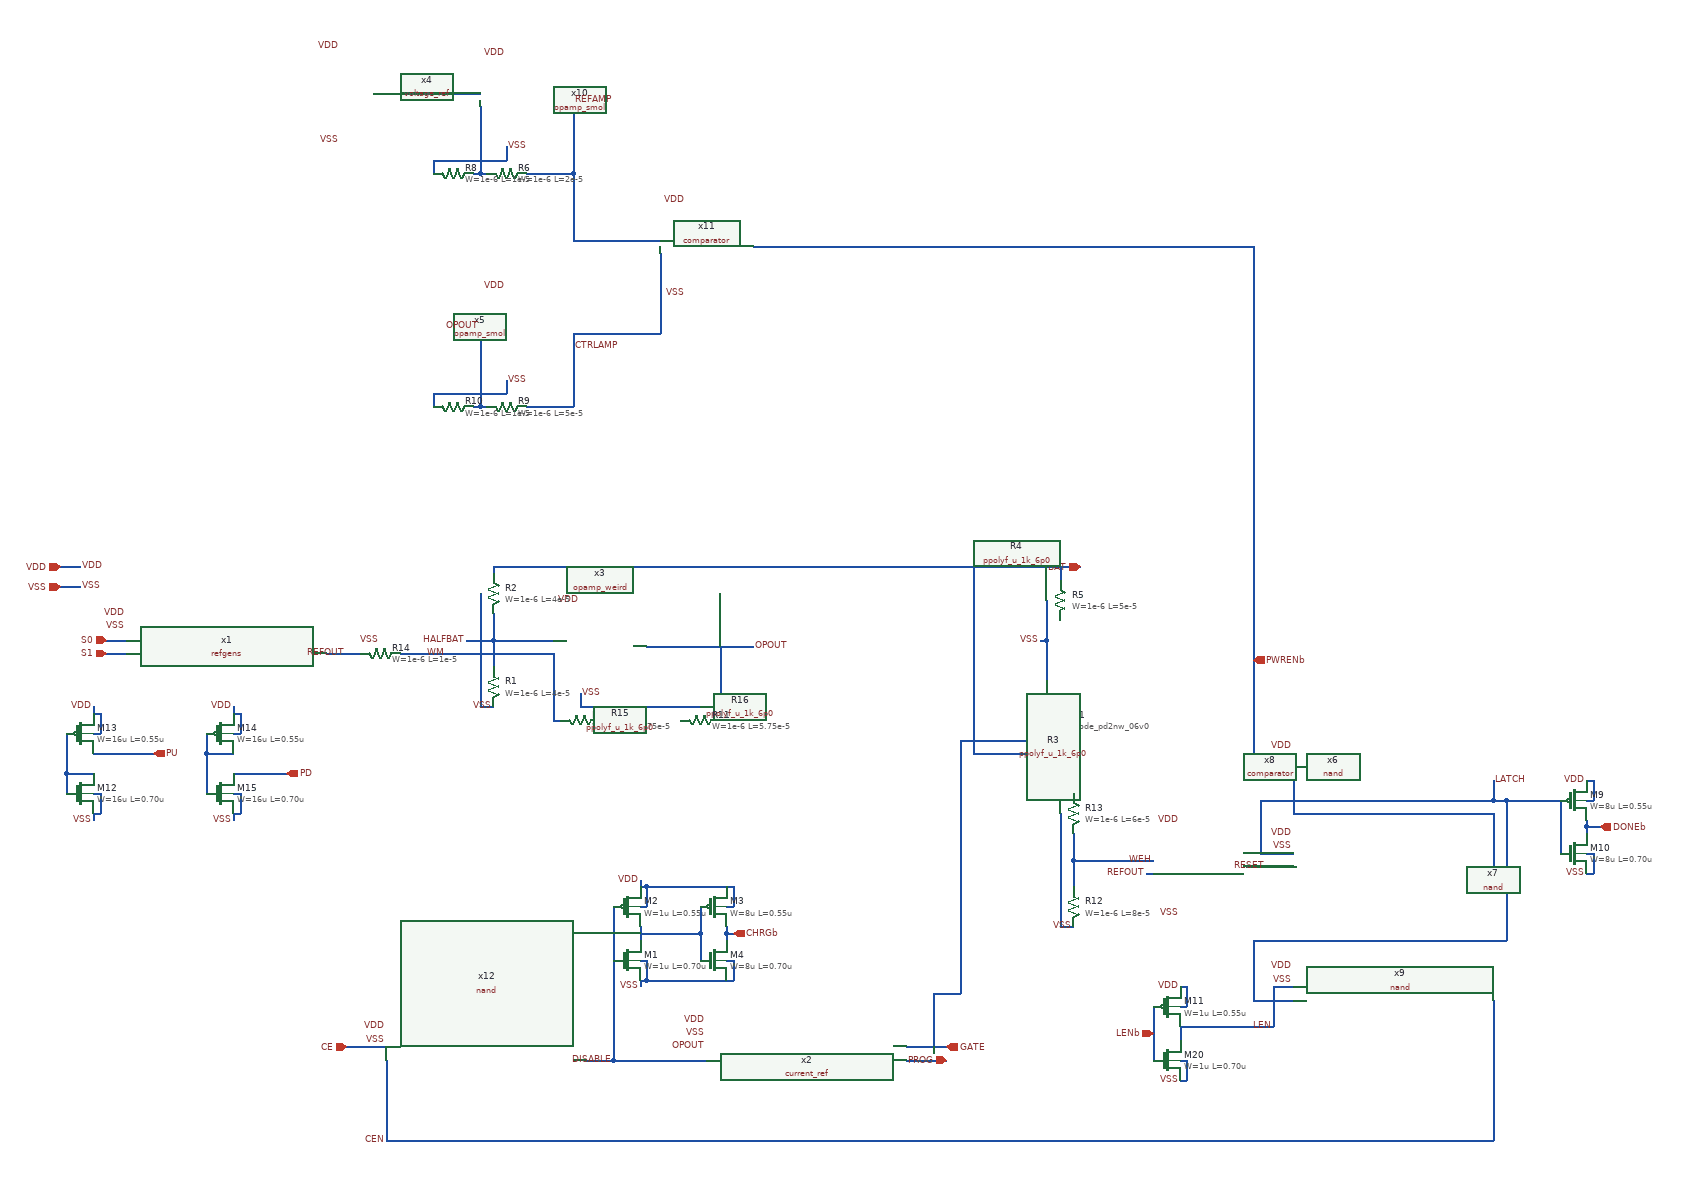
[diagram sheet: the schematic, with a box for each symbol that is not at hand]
v {xschem version=3.4.8RC file_version=1.3}
G {}
K {}
V {}
S {}
F {}
E {}
N -110 -10 -80 -10 {lab=VDD}
N -110 20 -80 20 {lab=VSS}
N -40 100 -10 100 {lab=S0}
N -40 120 -10 120 {lab=S1}
N 1160 710 1220 710 {lab=GATE}
N 720 730 860 730 {lab=DISABLE}
N 520 170 520 200 {lab=VSS}
N 520 200 540 200 {lab=VSS}
N 540 100 630 100 {lab=HALFBAT}
N 540 100 540 140 {lab=HALFBAT}
N 520 30 520 170 {lab=VSS}
N 540 60 540 100 {lab=HALFBAT}
N 540 -10 540 -0 {lab=BAT}
N 500 100 540 100 {lab=HALFBAT}
N 1360 100 1370 100 {lab=VSS}
N 1370 40 1370 100 {lab=VSS}
N 1370 100 1370 160 {lab=VSS}
N -60 360 -60 370 {lab=VSS}
N -100 300 -100 330 {lab=#net1}
N -100 300 -60 300 {lab=#net1}
N -60 360 -50 360 {lab=VSS}
N -50 330 -50 360 {lab=VSS}
N -60 330 -50 330 {lab=VSS}
N -100 240 -100 300 {lab=#net1}
N -60 240 -50 240 {lab=VDD}
N -50 210 -50 240 {lab=VDD}
N -60 210 -50 210 {lab=VDD}
N -60 200 -60 210 {lab=VDD}
N -60 270 30 270 {lab=PU}
N 150 200 150 210 {lab=VDD}
N 150 240 160 240 {lab=VDD}
N 160 210 160 240 {lab=VDD}
N 150 210 160 210 {lab=VDD}
N 110 240 110 270 {lab=#net2}
N 110 270 150 270 {lab=#net2}
N 110 270 110 330 {lab=#net2}
N 150 330 160 330 {lab=VSS}
N 160 330 160 360 {lab=VSS}
N 150 360 160 360 {lab=VSS}
N 150 360 150 370 {lab=VSS}
N 150 300 230 300 {lab=PD}
N 290 120 300 120 {lab=REFOUT}
N 1160 730 1220 730 {lab=PROG}
N 300 120 320 120 {lab=REFOUT}
N 540 -10 1420 -10 {lab=BAT}
N 2040 310 2040 340 {lab=LATCH}
N 1690 340 2040 340 {lab=LATCH}
N 1690 340 1690 420 {lab=LATCH}
N 1690 420 1740 420 {lab=LATCH}
N 1740 310 1740 360 {lab=#net3}
N 1740 360 2040 360 {lab=#net3}
N 2040 360 2040 440 {lab=#net3}
N 1670 440 1740 440 {lab=RESET}
N 1390 500 1390 530 {lab=VSS}
N 1390 530 1410 530 {lab=VSS}
N 1410 430 1410 470 {lab=WEH}
N 1390 360 1390 500 {lab=VSS}
N 1410 390 1410 430 {lab=WEH}
N 1410 320 1410 330 {lab=BAT}
N 1410 270 1410 320 {lab=BAT}
N 1260 270 1410 270 {lab=BAT}
N 1260 -10 1260 270 {lab=BAT}
N 1410 430 1530 430 {lab=WEH}
N 1520 450 1530 450 {lab=REFOUT}
N 1680 230 1680 290 {lab=PWRENb}
N 1680 290 1740 290 {lab=PWRENb}
N 2040 340 2060 340 {lab=LATCH}
N 2060 340 2060 550 {lab=LATCH}
N 1680 550 2060 550 {lab=LATCH}
N 2180 380 2200 380 {lab=DONEb}
N 2180 370 2180 380 {lab=DONEb}
N 2180 380 2180 390 {lab=DONEb}
N 2140 340 2140 420 {lab=LATCH}
N 2060 340 2140 340 {lab=LATCH}
N 2180 340 2190 340 {lab=VDD}
N 2190 310 2190 340 {lab=VDD}
N 2180 310 2190 310 {lab=VDD}
N 2180 450 2190 450 {lab=VSS}
N 2190 420 2190 450 {lab=VSS}
N 2180 420 2190 420 {lab=VSS}
N 1570 680 1570 700 {lab=#net4}
N 1570 650 1580 650 {lab=VDD}
N 1580 620 1580 650 {lab=VDD}
N 1570 620 1580 620 {lab=VDD}
N 1570 730 1580 730 {lab=VSS}
N 1580 730 1580 760 {lab=VSS}
N 1570 760 1580 760 {lab=VSS}
N 1530 650 1530 730 {lab=LENb}
N 1390 -10 1390 10 {lab=BAT}
N 1680 130 1680 230 {lab=PWRENb}
N 320 120 340 120 {lab=REFOUT}
N 400 120 630 120 {lab=WM}
N 670 180 670 200 {lab=VSS}
N 630 220 640 220 {lab=WM}
N 630 120 630 220 {lab=WM}
N 770 110 930 110 {lab=OPOUT}
N 880 110 880 220 {lab=OPOUT}
N 360 -720 520 -720 {lab=#net5}
N 560 -640 560 -620 {lab=VSS}
N 520 -700 520 -600 {lab=#net6}
N 510 -600 520 -600 {lab=#net6}
N 520 -600 530 -600 {lab=#net6}
N 480 -620 560 -620 {lab=VSS}
N 450 -620 480 -620 {lab=VSS}
N 450 -620 450 -600 {lab=VSS}
N 660 -710 660 -600 {lab=REFAMP}
N 590 -600 660 -600 {lab=REFAMP}
N 560 -290 560 -270 {lab=VSS}
N 520 -350 520 -250 {lab=#net7}
N 510 -250 520 -250 {lab=#net7}
N 520 -250 530 -250 {lab=#net7}
N 480 -270 560 -270 {lab=VSS}
N 450 -270 480 -270 {lab=VSS}
N 450 -270 450 -250 {lab=VSS}
N 660 -360 660 -250 {lab=CTRLAMP}
N 590 -250 660 -250 {lab=CTRLAMP}
N 1680 -490 1680 130 {lab=PWRENb}
N 930 -490 1680 -490 {lab=PWRENb}
N 660 -500 790 -500 {lab=REFAMP}
N 660 -600 660 -500 {lab=REFAMP}
N 660 -360 790 -360 {lab=CTRLAMP}
N 790 -480 790 -360 {lab=CTRLAMP}
N 670 200 790 200 {lab=VSS}
N 790 200 850 200 {lab=VSS}
N 680 730 720 730 {lab=DISABLE}
N 320 710 380 710 {lab=CE}
N 2040 640 2040 850 {lab=#net8}
N 380 850 2040 850 {lab=#net8}
N 380 730 380 850 {lab=#net8}
N 720 500 720 730 {lab=DISABLE}
N 760 610 760 620 {lab=VSS}
N 760 610 770 610 {lab=VSS}
N 770 580 770 610 {lab=VSS}
N 760 580 770 580 {lab=VSS}
N 760 460 760 470 {lab=VDD}
N 760 470 770 470 {lab=VDD}
N 770 470 770 500 {lab=VDD}
N 760 500 770 500 {lab=VDD}
N 760 530 760 550 {lab=#net9}
N 770 470 890 470 {lab=VDD}
N 890 500 900 500 {lab=VDD}
N 900 470 900 500 {lab=VDD}
N 890 470 900 470 {lab=VDD}
N 770 610 890 610 {lab=VSS}
N 890 610 900 610 {lab=VSS}
N 900 580 900 610 {lab=VSS}
N 890 580 900 580 {lab=VSS}
N 760 540 850 540 {lab=#net9}
N 850 500 850 540 {lab=#net9}
N 850 540 850 580 {lab=#net9}
N 890 540 900 540 {lab=CHRGb}
N 890 530 890 540 {lab=CHRGb}
N 890 540 890 550 {lab=CHRGb}
N 1570 680 1710 680 {lab=#net4}
N 1710 620 1710 680 {lab=#net4}
N 1710 620 1740 620 {lab=#net4}
N 1680 550 1680 640 {lab=LATCH}
N 1680 640 1740 640 {lab=LATCH}
N 1240 250 1390 250 {lab=GATE}
N 1240 250 1240 630 {lab=GATE}
N 1200 630 1240 630 {lab=GATE}
N 1200 630 1200 710 {lab=GATE}
C {iopin.sym} -110 -10 2 0 {name=p1 lab=VDD}
C {lab_pin.sym} -80 -10 2 0 {name=p2 sig_type=std_logic lab=VDD}
C {iopin.sym} -110 20 2 0 {name=p3 lab=VSS}
C {lab_pin.sym} -80 20 2 0 {name=p4 sig_type=std_logic lab=VSS}
C {ipin.sym} -40 100 0 0 {name=p5 lab=S0}
C {ipin.sym} -40 120 0 0 {name=p6 lab=S1}
C {ipin.sym} 1530 690 0 0 {name=p7 lab=LENb}
C {ipin.sym} 320 710 0 0 {name=p8 lab=CE}
C {opin.sym} 900 540 0 0 {name=p9 lab=CHRGb}
C {opin.sym} 2200 380 0 0 {name=p10 lab=DONEb}
C {iopin.sym} 1220 730 0 0 {name=p11 lab=PROG}
C {opin.sym} 1680 130 0 0 {name=p12 lab=PWRENb}
C {refgens.sym} 140 100 0 0 {name=x1}
C {lab_pin.sym} -10 60 0 0 {name=p13 sig_type=std_logic lab=VDD}
C {lab_pin.sym} -10 80 0 0 {name=p14 sig_type=std_logic lab=VSS}
C {opin.sym} 1220 710 0 0 {name=p15 lab=GATE}
C {ipin.sym} 1420 -10 2 0 {name=p16 lab=BAT}
C {current_ref.sym} 1010 700 0 0 {name=x2}
C {lab_pin.sym} 860 670 0 0 {name=p17 sig_type=std_logic lab=VDD}
C {lab_pin.sym} 670 40 1 0 {name=p23 sig_type=std_logic lab=VDD}
C {lab_pin.sym} 670 180 2 0 {name=p24 sig_type=std_logic lab=VSS}
C {symbols/ppolyf_u_1k_6p0.sym} 540 170 0 0 {name=R1
W=1e-6
L=4e-5
model=ppolyf_u_1k_6p0
spiceprefix=X
m=1}
C {lab_pin.sym} 540 200 3 0 {name=p25 sig_type=std_logic lab=VSS}
C {symbols/ppolyf_u_1k_6p0.sym} 540 30 0 0 {name=R2
W=1e-6
L=4e-5
model=ppolyf_u_1k_6p0
spiceprefix=X
m=1}
C {lab_pin.sym} 320 120 1 0 {name=p30 sig_type=std_logic lab=REFOUT}
C {lab_pin.sym} 500 100 0 0 {name=p31 sig_type=std_logic lab=HALFBAT}
C {symbols/diode_pd2nw_06v0.sym} 1390 220 0 0 {name=D1
model=diode_pd2nw_06v0
r_w=2u
r_l=1u
m=1}
C {symbols/ppolyf_u_1k_6p0.sym} 1390 160 0 0 {name=R3
W=1e-6
L=5e-5
model=ppolyf_u_1k_6p0
spiceprefix=X
m=1}
C {symbols/ppolyf_u_1k_6p0.sym} 1390 100 0 0 {name=R4
W=1e-6
L=5e-5
model=ppolyf_u_1k_6p0
spiceprefix=X
m=1}
C {symbols/ppolyf_u_1k_6p0.sym} 1390 40 0 0 {name=R5
W=1e-6
L=5e-5
model=ppolyf_u_1k_6p0
spiceprefix=X
m=1}
C {lab_pin.sym} 1360 100 0 0 {name=p32 sig_type=std_logic lab=VSS}
C {opin.sym} 30 270 0 0 {name=p34 lab=PU}
C {opin.sym} 230 300 0 0 {name=p35 lab=PD}
C {symbols/nfet_06v0.sym} -80 330 0 0 {name=M12
L=0.70u
W=16u
nf=2
m=1
ad="'int((nf+1)/2) * W/nf * 0.18u'"
pd="'2*int((nf+1)/2) * (W/nf + 0.18u)'"
as="'int((nf+2)/2) * W/nf * 0.18u'"
ps="'2*int((nf+2)/2) * (W/nf + 0.18u)'"
nrd="'0.18u / W'" nrs="'0.18u / W'"
sa=0 sb=0 sd=0
model=nfet_06v0
spiceprefix=X
}
C {lab_pin.sym} -60 370 3 0 {name=p38 sig_type=std_logic lab=VSS}
C {symbols/pfet_06v0.sym} -80 240 0 0 {name=M13
L=0.55u
W=16u
nf=2
m=1
ad="'int((nf+1)/2) * W/nf * 0.18u'"
pd="'2*int((nf+1)/2) * (W/nf + 0.18u)'"
as="'int((nf+2)/2) * W/nf * 0.18u'"
ps="'2*int((nf+2)/2) * (W/nf + 0.18u)'"
nrd="'0.18u / W'" nrs="'0.18u / W'"
sa=0 sb=0 sd=0
model=pfet_06v0
spiceprefix=X
}
C {lab_pin.sym} -60 200 1 0 {name=p39 sig_type=std_logic lab=VDD}
C {symbols/pfet_06v0.sym} 130 240 0 0 {name=M14
L=0.55u
W=16u
nf=2
m=1
ad="'int((nf+1)/2) * W/nf * 0.18u'"
pd="'2*int((nf+1)/2) * (W/nf + 0.18u)'"
as="'int((nf+2)/2) * W/nf * 0.18u'"
ps="'2*int((nf+2)/2) * (W/nf + 0.18u)'"
nrd="'0.18u / W'" nrs="'0.18u / W'"
sa=0 sb=0 sd=0
model=pfet_06v0
spiceprefix=X
}
C {lab_pin.sym} 150 200 1 0 {name=p40 sig_type=std_logic lab=VDD}
C {symbols/nfet_06v0.sym} 130 330 0 0 {name=M15
L=0.70u
W=16u
nf=2
m=1
ad="'int((nf+1)/2) * W/nf * 0.18u'"
pd="'2*int((nf+1)/2) * (W/nf + 0.18u)'"
as="'int((nf+2)/2) * W/nf * 0.18u'"
ps="'2*int((nf+2)/2) * (W/nf + 0.18u)'"
nrd="'0.18u / W'" nrs="'0.18u / W'"
sa=0 sb=0 sd=0
model=nfet_06v0
spiceprefix=X
}
C {lab_pin.sym} 150 370 3 0 {name=p41 sig_type=std_logic lab=VSS}
C {lab_pin.sym} 860 690 0 0 {name=p18 sig_type=std_logic lab=VSS}
C {lab_pin.sym} 930 110 2 0 {name=p28 sig_type=std_logic lab=OPOUT}
C {nand.sym} 1890 290 0 0 {name=x6}
C {nand.sym} 1890 420 0 0 {name=x7}
C {lab_pin.sym} 1740 260 0 0 {name=p52 sig_type=std_logic lab=VDD}
C {lab_pin.sym} 1740 390 0 0 {name=p53 sig_type=std_logic lab=VDD}
C {lab_pin.sym} 1740 280 0 0 {name=p54 sig_type=std_logic lab=VSS}
C {lab_pin.sym} 1740 410 0 0 {name=p55 sig_type=std_logic lab=VSS}
C {comparator.sym} 1680 440 0 0 {name=x8}
C {lab_pin.sym} 1570 370 1 0 {name=p57 sig_type=std_logic lab=VDD}
C {lab_pin.sym} 1570 510 3 0 {name=p58 sig_type=std_logic lab=VSS}
C {lab_pin.sym} 1520 450 0 0 {name=p59 sig_type=std_logic lab=REFOUT}
C {symbols/ppolyf_u_1k_6p0.sym} 1410 500 0 0 {name=R12
W=1e-6
L=8e-5
model=ppolyf_u_1k_6p0
spiceprefix=X
m=1}
C {lab_pin.sym} 1410 530 3 0 {name=p60 sig_type=std_logic lab=VSS}
C {symbols/ppolyf_u_1k_6p0.sym} 1410 360 0 0 {name=R13
W=1e-6
L=6e-5
model=ppolyf_u_1k_6p0
spiceprefix=X
m=1}
C {lab_pin.sym} 1700 440 3 0 {name=p62 sig_type=std_logic lab=RESET}
C {lab_pin.sym} 2040 310 2 0 {name=p63 sig_type=std_logic lab=LATCH}
C {nand.sym} 1890 620 0 0 {name=x9}
C {lab_pin.sym} 1740 590 0 0 {name=p66 sig_type=std_logic lab=VDD}
C {lab_pin.sym} 1740 610 0 0 {name=p67 sig_type=std_logic lab=VSS}
C {symbols/pfet_06v0.sym} 2160 340 0 0 {name=M9
L=0.55u
W=8u
nf=1
m=1
ad="'int((nf+1)/2) * W/nf * 0.18u'"
pd="'2*int((nf+1)/2) * (W/nf + 0.18u)'"
as="'int((nf+2)/2) * W/nf * 0.18u'"
ps="'2*int((nf+2)/2) * (W/nf + 0.18u)'"
nrd="'0.18u / W'" nrs="'0.18u / W'"
sa=0 sb=0 sd=0
model=pfet_06v0
spiceprefix=X
}
C {symbols/nfet_06v0.sym} 2160 420 0 0 {name=M10
L=0.70u
W=8u
nf=1
m=1
ad="'int((nf+1)/2) * W/nf * 0.18u'"
pd="'2*int((nf+1)/2) * (W/nf + 0.18u)'"
as="'int((nf+2)/2) * W/nf * 0.18u'"
ps="'2*int((nf+2)/2) * (W/nf + 0.18u)'"
nrd="'0.18u / W'" nrs="'0.18u / W'"
sa=0 sb=0 sd=0
model=nfet_06v0
spiceprefix=X
}
C {lab_pin.sym} 2180 310 1 0 {name=p26 sig_type=std_logic lab=VDD}
C {lab_pin.sym} 2180 450 3 0 {name=p71 sig_type=std_logic lab=VSS}
C {symbols/pfet_06v0.sym} 1550 650 0 0 {name=M11
L=0.55u
W=1u
nf=1
m=1
ad="'int((nf+1)/2) * W/nf * 0.18u'"
pd="'2*int((nf+1)/2) * (W/nf + 0.18u)'"
as="'int((nf+2)/2) * W/nf * 0.18u'"
ps="'2*int((nf+2)/2) * (W/nf + 0.18u)'"
nrd="'0.18u / W'" nrs="'0.18u / W'"
sa=0 sb=0 sd=0
model=pfet_06v0
spiceprefix=X
}
C {symbols/nfet_06v0.sym} 1550 730 0 0 {name=M20
L=0.70u
W=1u
nf=1
m=1
ad="'int((nf+1)/2) * W/nf * 0.18u'"
pd="'2*int((nf+1)/2) * (W/nf + 0.18u)'"
as="'int((nf+2)/2) * W/nf * 0.18u'"
ps="'2*int((nf+2)/2) * (W/nf + 0.18u)'"
nrd="'0.18u / W'" nrs="'0.18u / W'"
sa=0 sb=0 sd=0
model=nfet_06v0
spiceprefix=X
}
C {lab_pin.sym} 1570 620 1 0 {name=p72 sig_type=std_logic lab=VDD}
C {lab_pin.sym} 1570 760 3 0 {name=p73 sig_type=std_logic lab=VSS}
C {lab_pin.sym} 860 710 0 0 {name=p75 sig_type=std_logic lab=OPOUT}
C {symbols/ppolyf_u_1k_6p0.sym} 670 220 1 0 {name=R7
W=1e-6
L=5.75e-5
model=ppolyf_u_1k_6p0
spiceprefix=X
m=1}
C {symbols/ppolyf_u_1k_6p0.sym} 370 120 1 0 {name=R14
W=1e-6
L=1e-5
model=ppolyf_u_1k_6p0
spiceprefix=X
m=1}
C {lab_pin.sym} 370 100 0 0 {name=p74 sig_type=std_logic lab=VSS}
C {symbols/ppolyf_u_1k_6p0.sym} 730 220 1 0 {name=R15
W=1e-6
L=5.75e-5
model=ppolyf_u_1k_6p0
spiceprefix=X
m=1}
C {symbols/ppolyf_u_1k_6p0.sym} 790 220 1 0 {name=R16
W=1e-6
L=5.75e-5
model=ppolyf_u_1k_6p0
spiceprefix=X
m=1}
C {opamp_weird.sym} 780 110 0 0 {name=x3}
C {lab_pin.sym} 470 120 0 0 {name=p84 sig_type=std_logic lab=WM}
C {lab_pin.sym} 1530 430 1 0 {name=p56 sig_type=std_logic lab=WEH}
C {voltage_ref.sym} 420 -720 0 0 {name=x4}
C {lab_pin.sym} 310 -790 1 0 {name=p33 sig_type=std_logic lab=VDD}
C {lab_pin.sym} 310 -650 3 0 {name=p36 sig_type=std_logic lab=VSS}
C {opamp_smol.sym} 670 -710 0 0 {name=x10}
C {lab_pin.sym} 560 -780 1 0 {name=p48 sig_type=std_logic lab=VDD}
C {lab_pin.sym} 560 -640 2 0 {name=p50 sig_type=std_logic lab=VSS}
C {symbols/ppolyf_u_1k_6p0.sym} 560 -600 1 0 {name=R6
W=1e-6
L=2e-5
model=ppolyf_u_1k_6p0
spiceprefix=X
m=1}
C {symbols/ppolyf_u_1k_6p0.sym} 480 -600 1 0 {name=R8
W=1e-6
L=1e-5
model=ppolyf_u_1k_6p0
spiceprefix=X
m=1}
C {opamp_smol.sym} 670 -360 0 0 {name=x5}
C {lab_pin.sym} 560 -430 1 0 {name=p37 sig_type=std_logic lab=VDD}
C {lab_pin.sym} 560 -290 2 0 {name=p44 sig_type=std_logic lab=VSS}
C {symbols/ppolyf_u_1k_6p0.sym} 560 -250 1 0 {name=R9
W=1e-6
L=5e-5
model=ppolyf_u_1k_6p0
spiceprefix=X
m=1}
C {symbols/ppolyf_u_1k_6p0.sym} 480 -250 1 0 {name=R10
W=1e-6
L=1e-5
model=ppolyf_u_1k_6p0
spiceprefix=X
m=1}
C {lab_pin.sym} 520 -370 0 0 {name=p45 sig_type=std_logic lab=OPOUT}
C {comparator.sym} 940 -490 0 0 {name=x11}
C {lab_pin.sym} 830 -560 1 0 {name=p46 sig_type=std_logic lab=VDD}
C {lab_pin.sym} 830 -420 3 0 {name=p47 sig_type=std_logic lab=VSS}
C {lab_pin.sym} 660 -710 2 0 {name=p51 sig_type=std_logic lab=REFAMP}
C {lab_pin.sym} 660 -340 2 0 {name=p64 sig_type=std_logic lab=CTRLAMP}
C {symbols/ppolyf_u_1k_6p0.sym} 850 220 1 0 {name=R11
W=1e-6
L=5.75e-5
model=ppolyf_u_1k_6p0
spiceprefix=X
m=1}
C {nand.sym} 530 710 0 0 {name=x12}
C {lab_pin.sym} 380 680 0 0 {name=p19 sig_type=std_logic lab=VDD}
C {lab_pin.sym} 380 700 0 0 {name=p20 sig_type=std_logic lab=VSS}
C {symbols/nfet_06v0.sym} 740 580 0 0 {name=M1
L=0.70u
W=1u
nf=1
m=1
ad="'int((nf+1)/2) * W/nf * 0.18u'"
pd="'2*int((nf+1)/2) * (W/nf + 0.18u)'"
as="'int((nf+2)/2) * W/nf * 0.18u'"
ps="'2*int((nf+2)/2) * (W/nf + 0.18u)'"
nrd="'0.18u / W'" nrs="'0.18u / W'"
sa=0 sb=0 sd=0
model=nfet_06v0
spiceprefix=X
}
C {symbols/pfet_06v0.sym} 740 500 0 0 {name=M2
L=0.55u
W=1u
nf=1
m=1
ad="'int((nf+1)/2) * W/nf * 0.18u'"
pd="'2*int((nf+1)/2) * (W/nf + 0.18u)'"
as="'int((nf+2)/2) * W/nf * 0.18u'"
ps="'2*int((nf+2)/2) * (W/nf + 0.18u)'"
nrd="'0.18u / W'" nrs="'0.18u / W'"
sa=0 sb=0 sd=0
model=pfet_06v0
spiceprefix=X
}
C {lab_pin.sym} 760 620 3 0 {name=p21 sig_type=std_logic lab=VSS}
C {lab_pin.sym} 760 460 1 0 {name=p22 sig_type=std_logic lab=VDD}
C {symbols/pfet_06v0.sym} 870 500 0 0 {name=M3
L=0.55u
W=8u
nf=1
m=1
ad="'int((nf+1)/2) * W/nf * 0.18u'"
pd="'2*int((nf+1)/2) * (W/nf + 0.18u)'"
as="'int((nf+2)/2) * W/nf * 0.18u'"
ps="'2*int((nf+2)/2) * (W/nf + 0.18u)'"
nrd="'0.18u / W'" nrs="'0.18u / W'"
sa=0 sb=0 sd=0
model=pfet_06v0
spiceprefix=X
}
C {symbols/nfet_06v0.sym} 870 580 0 0 {name=M4
L=0.70u
W=8u
nf=1
m=1
ad="'int((nf+1)/2) * W/nf * 0.18u'"
pd="'2*int((nf+1)/2) * (W/nf + 0.18u)'"
as="'int((nf+2)/2) * W/nf * 0.18u'"
ps="'2*int((nf+2)/2) * (W/nf + 0.18u)'"
nrd="'0.18u / W'" nrs="'0.18u / W'"
sa=0 sb=0 sd=0
model=nfet_06v0
spiceprefix=X
}
C {lab_pin.sym} 720 730 3 0 {name=p27 sig_type=std_logic lab=DISABLE}
C {lab_pin.sym} 1710 680 3 0 {name=p29 sig_type=std_logic lab=LEN}
C {lab_pin.sym} 380 850 3 0 {name=p42 sig_type=std_logic lab=CEN}
